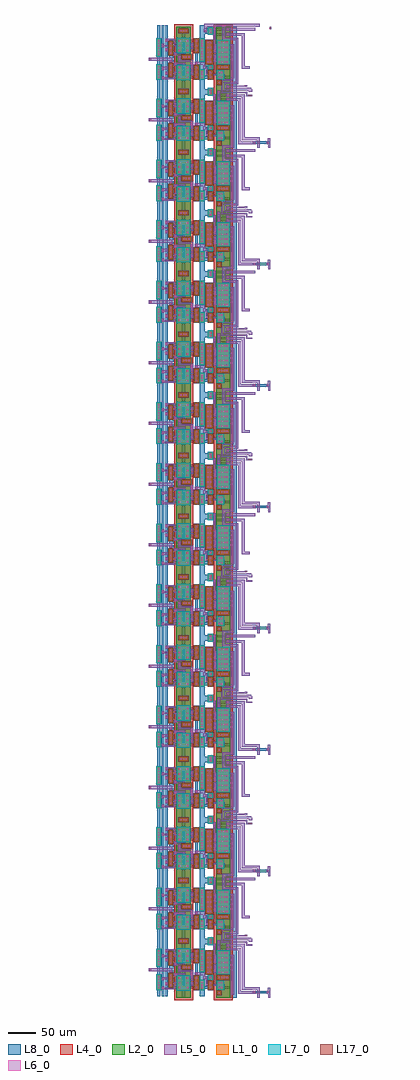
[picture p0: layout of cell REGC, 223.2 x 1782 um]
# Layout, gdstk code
from math import pi, radians
import gdstk
lib = gdstk.Library(unit=1e-6, precision=1e-09)
def R(c, l, rs):  # rectangles x0, y0, x1, y1
    for r in rs: c.add(gdstk.rectangle(r[:2], r[2:], *l))
def A(c, l, x, y, w, h, nx, ny, dx, dy):  # array of equal rectangles
    R(c, l, [(x+i*dx, y+j*dy, x+i*dx+w, y+j*dy+h) for i in range(nx) for j in range(ny)])
def P(c, l, *ps):  # polygons
    for p in ps: c.add(gdstk.Polygon(p, *l))
L1_0 = (1, 0)
L2_0 = (2, 0)
L4_0 = (4, 0)
L5_0 = (5, 0)
L6_0 = (6, 0)
L7_0 = (7, 0)
L8_0 = (8, 0)
L17_0 = (17, 0)

regbg = lib.new_cell('REGBG')
R(regbg, L1_0, [(44,8.4,51.2,20.4), (88,10.4,104.8,17.6), (58.8,28.8,66.4,69.6), (69.6,28.8,76.8,53.6), (138.4,28.8,145.6,60), (13.6,32,35.2,74.4), (44,32,55.6,74.4), (116.4,33.2,123.6,58), (83.2,58.4,100,65.6), (116.4,73.2,123.6,98), (138.4,76,145.6,102.4), (13.6,76.8,35.2,84), (44,76.8,51.2,84), (69.6,77.6,76.8,102.4), (58.8,85.6,66.4,102.4), (23.6,86.4,35.2,102.4), (44,86.4,51.2,102.4), (28,104.8,35.2,112)])
P(regbg, L1_0, [(107.6,103.2),(107.6,77.6),(100.4,77.6),(100.4,96.8),(92.8,96.8),(92.8,77.6),(85.6,77.6),(85.6,103.2)],
  [(107.6,28),(107.6,53.6),(100.4,53.6),(100.4,34.4),(92.8,34.4),(92.8,53.6),(85.6,53.6),(85.6,28)])
R(regbg, L2_0, [(11.6,6.4,37.2,117.2), (83.6,6.4,109.6,117.2)])
R(regbg, L4_0, [(7.2,2,41.6,121.6), (79.2,2,114,121.6)])
P(regbg, L5_0, [(78.8,88.8),(78.8,93.2),(67.6,93.2),(67.6,95.6),(94.8,95.6),(94.8,93.2),(84.4,93.2),(84.4,88.8)],
  [(160,68.8),(160,63.2),(117.2,63.2),(117.2,72),(122.8,72),(122.8,68.8)],
  [(124.8,91.2),(124.8,94.4),(130.4,94.4),(130.4,88.8),(111.2,88.8),(111.2,84.4),(98.4,84.4),(98.4,86.8),(108.8,86.8),(108.8,91.2)],
  [(84.4,70.4),(106.8,70.4),(106.8,59.2),(101.2,59.2),(101.2,67.2),(78.8,67.2),(78.8,82.4),(84.4,82.4)],
  [(108.8,58.8),(108.8,57.2),(94,57.2),(94,46.8),(67.6,46.8),(67.6,44.4),(96.4,44.4),(96.4,54.8),(108.8,54.8),(108.8,53.2),(114.4,53.2),(114.4,58.8)],
  [(131.6,85.6),(131.6,84),(124.8,84),(124.8,82.4),(114.4,82.4),(114.4,80),(137.2,80),(137.2,85.6)],
  [(78.8,42.4),(78.8,38),(67.6,38),(67.6,35.6),(94.8,35.6),(94.8,38),(84.4,38),(84.4,42.4)],
  [(131.6,40),(131.6,38),(137.2,38),(137.2,43.6),(131.6,43.6),(131.6,42.4),(111.2,42.4),(111.2,46.8),(98.4,46.8),(98.4,44.4),(108.8,44.4),(108.8,40)],
  [(36.4,58.8),(36.4,65.2),(11.6,65.2),(11.6,67.6),(36.4,67.6),(36.4,71.6),(42,71.6),(42,67.6),(57.6,67.6),(57.6,65.2),(42,65.2),(42,58.8),(57.6,58.8),(57.6,56.4),(11.6,56.4),(11.6,58.8)],
  [(94,84.4),(67.6,84.4),(67.6,86.8),(96.4,86.8),(96.4,76.4),(108.8,76.4),(108.8,78),(114.4,78),(114.4,72.4),(94,72.4)],
  [(60.8,84.4),(56.4,84.4),(56.4,95.6),(21.6,95.6),(21.6,93.2),(53.2,93.2),(53.2,79.2),(56.8,79.2),(56.8,70.8),(76,70.8),(76,76.4),(60.8,76.4)],
  [(131.6,96.8),(137.2,96.8),(137.2,102.4),(112,102.4),(112,95.6),(98.4,95.6),(98.4,93.2),(115.1,93.2),(115.1,99.2),(131.6,99.2)],
  [(130.4,34.4),(124.8,34.4),(124.8,32),(115.1,32),(115.1,38),(98.4,38),(98.4,35.6),(112,35.6),(112,28.8),(130.4,28.8)],
  [(130.4,45.6),(130.4,51.2),(114.4,51.2),(114.4,48.8),(124.8,48.8),(124.8,45.6)],
  [(57.6,38.8),(9.2,38.8),(9.2,41.2),(36.4,41.2),(36.4,47.6),(9.2,47.6),(9.2,50),(36.4,50),(36.4,54),(42,54),(42,50),(57.6,50),(57.6,47.6),(42,47.6),(42,41.2),(57.6,41.2)])
A(regbg, L6_0, 90.4, 12.8, 2.4, 2.4, 3, 1, 4.8, 0)
A(regbg, L6_0, 61.2, 31.2, 2.8, 2.4, 1, 8, 0, 4.8)
A(regbg, L6_0, 72, 31.2, 2.4, 2.4, 1, 3, 0, 8.8)
A(regbg, L6_0, 88, 31.2, 2.4, 2.4, 1, 3, 0, 8.8)
A(regbg, L6_0, 102.8, 31.2, 2.4, 2.4, 1, 3, 0, 8.8)
A(regbg, L6_0, 140.8, 31.2, 2.4, 2.4, 1, 6, 0, 4.8)
A(regbg, L6_0, 16, 34.4, 2.4, 2.4, 1, 3, 0, 8.8)
A(regbg, L6_0, 16, 34.4, 2.4, 2.4, 4, 5, 4.8, 8.8)
A(regbg, L6_0, 46.4, 34.4, 2.4, 2.4, 1, 5, 0, 8.8)
A(regbg, L6_0, 50.8, 34.4, 2.4, 2.4, 1, 5, 0, 8.8)
A(regbg, L6_0, 118.8, 35.6, 2.4, 2.4, 1, 3, 0, 8.8)
A(regbg, L6_0, 16, 52, 2.4, 2.4, 1, 3, 0, 8.8)
A(regbg, L6_0, 85.6, 60.8, 2.4, 2.4, 3, 1, 4.8, 0)
A(regbg, L6_0, 118.8, 75.6, 2.4, 2.4, 1, 3, 0, 8.8)
A(regbg, L6_0, 140.8, 78.4, 2.4, 2.4, 1, 5, 0, 4.8)
A(regbg, L6_0, 16, 79.2, 2.4, 2.4, 4, 1, 4.8, 0)
A(regbg, L6_0, 72, 80, 2.4, 2.4, 1, 3, 0, 8.8)
A(regbg, L6_0, 88, 80, 2.4, 2.4, 1, 3, 0, 8.8)
A(regbg, L6_0, 102.8, 80, 2.4, 2.4, 1, 3, 0, 8.8)
A(regbg, L6_0, 61.2, 88, 2.8, 2.4, 1, 3, 0, 4.8)
R(regbg, L6_0, [(46.4,10.8,48.8,13.2), (46.4,15.6,48.8,18), (126.4,30.4,128.8,32.8), (80.4,38.4,82.8,40.8), (133.2,39.6,135.6,42), (126.4,47.2,128.8,49.6), (38,50,40.4,52.4), (110.4,54.8,112.8,57.2), (102.8,60.8,105.2,63.2), (156,64.8,158.4,67.2), (38,67.6,40.4,70), (118.8,68,121.2,70.4), (72,72.4,74.4,74.8), (110.4,74,112.8,76.4), (80.4,78.4,82.8,80.8), (16,79.2,18.4,81.6), (46.4,79.2,48.8,81.6), (133.2,81.6,135.6,84), (26,88.8,28.4,91.2), (30.4,88.8,32.8,91.2), (46.4,88.8,48.8,91.2), (80.4,90.4,82.8,92.8), (126.4,90.4,128.8,92.8), (26,97.6,28.4,100), (30.4,97.6,32.8,100), (46.4,97.6,48.8,100), (133.2,98.4,135.6,100.8), (30.4,107.2,32.8,109.6)])
R(regbg, L7_0, [(42.8,7.2,52.4,21.6), (84.4,26.8,108.8,54.8), (57.6,27.6,67.6,70.8), (137.2,27.6,146.8,61.2), (12.4,30.8,36.4,75.6), (137.2,74.8,146.8,103.6), (42.8,75.6,52.4,85.2), (84.4,76.4,108.8,104.4), (57.6,84.4,67.6,103.6), (22.4,85.2,36.4,103.6)])
A(regbg, L8_0, 12, 33.2, 22, 4.8, 1, 3, 0, 17.6)
A(regbg, L8_0, 45.2, 33.2, 12.8, 4.8, 1, 3, 0, 17.6)
R(regbg, L8_0, [(125.2,4,130,114.8), (132,4,136.8,114.8), (139.2,4,144.8,114.8), (0,6.4,12,117.2), (70.8,30,91.6,34.8), (67.2,38.8,75.6,43.6), (12,78,34,82.8), (45.2,78,58,82.8), (67.2,87.6,75.6,92.4), (45.2,96.4,58,101.2), (70.8,96.4,91.6,101.2)])
P(regbg, L8_0, [(91.6,52.4),(75.6,52.4),(75.6,76),(70.8,76),(70.8,47.6),(79.2,47.6),(79.2,37.2),(84,37.2),(84,47.6),(91.6,47.6)],
  [(122.4,88),(122.4,83.2),(114,83.2),(114,72.8),(109.2,72.8),(109.2,87.6),(101.6,87.6),(101.6,92.4),(114,92.4),(114,88)],
  [(122.4,92),(122.4,101.2),(101.6,101.2),(101.6,96.4),(117.6,96.4),(117.6,92)],
  [(34,110.8),(34,96.4),(12,96.4),(12,101.2),(29.2,101.2),(29.2,110.8)],
  [(84,78.8),(84,77.2),(79.2,77.2),(79.2,78.8),(70.8,78.8),(70.8,83.6),(79.2,83.6),(79.2,94),(84,94),(84,83.6),(91.6,83.6),(91.6,78.8)],
  [(122.4,66.8),(101.6,66.8),(101.6,83.6),(106.4,83.6),(106.4,70.8),(117.6,70.8),(117.6,79.2),(122.4,79.2)],
  [(93.6,11.6),(89.2,11.6),(89.2,16.4),(93.6,16.4),(93.6,38.8),(86.8,38.8),(86.8,43.8),(93.6,43.8),(93.6,59.6),(84.4,59.6),(84.4,64.4),(93.6,64.4),(93.6,87.6),(86.8,87.6),(86.8,92.4),(93.6,92.4),(93.6,117.2),(99.6,117.2),(99.6,16.4),(103.6,16.4),(103.6,11.6),(99.6,11.6),(99.6,6.4),(93.6,6.4)],
  [(122.4,43.2),(122.4,48),(114,48),(114,58.4),(109.2,58.4),(109.2,43.6),(101.6,43.6),(101.6,38.8),(114,38.8),(114,43.2)],
  [(122.4,39.2),(122.4,30),(101.6,30),(101.6,34.8),(117.6,34.8),(117.6,39.2)],
  [(122.4,64.4),(101.6,64.4),(101.6,47.6),(106.4,47.6),(106.4,60.4),(117.6,60.4),(117.6,52),(122.4,52)],
  [(41.6,59.6),(41.6,48.8),(36.8,48.8),(36.8,59.6),(14.8,59.6),(14.8,64.4),(54.4,64.4),(54.4,59.6)],
  [(67.2,114.8),(67.2,4),(58,4),(58,9.6),(44.8,9.6),(44.8,19.6),(58,19.6),(58,114.8)],
  [(41.6,87.6),(41.6,66.4),(36.8,66.4),(36.8,87.6),(24.4,87.6),(24.4,92.4),(50,92.4),(50,87.6)],
  [(40.8,42),(40.8,32.4),(36.8,32.4),(36.8,42),(14.8,42),(14.8,46.8),(54.4,46.8),(54.4,42)])
R(regbg, L17_0, [(86.8,9.2,106,18.8), (68.4,27.6,78,54.8), (42.8,30.8,56.8,75.6), (115.2,32,124.8,59.2), (82,57.2,101.2,66.8), (115.2,72,124.8,99.2), (12.4,75.6,36.4,85.2), (68.4,76.4,78,103.6), (42.8,85.2,52.4,103.6), (26.8,103.6,36.4,113.2)])
regbg.add(gdstk.Label('REGBG', (167.6,65.6), layer=58, texttype=0))
regbg.add(gdstk.Label('HB', (134.4,111.85), layer=59, texttype=0))
regbg.add(gdstk.Label('H', (127.55,110.95), layer=59, texttype=0))
regbg.add(gdstk.Label('VDD', (96.6,23.05), layer=60, texttype=0))
regbg.add(gdstk.Label('VSS', (62.4,21.35), layer=60, texttype=0))
regbg.add(gdstk.Label('VDD', (6.4,57.2), layer=60, texttype=0))
regbg.add(gdstk.Label('VSS', (142.4,22.15), layer=60, texttype=0))

doublregbg = lib.new_cell('DOUBLREGBG')
R(doublregbg, L5_0, [(178.4,10.4,183.6,15.6), (105.6,81.6,110.8,101.6), (113.6,89.2,118.8,108), (129.6,89.2,134.8,94.4), (129.6,96.4,134.8,101.6), (129.6,112.4,134.8,118), (105.6,192.4,110.8,222.4), (129.6,208,134.8,213.2), (129.6,217.2,134.8,222.4)])
P(doublregbg, L5_0, [(209.6,21.2),(209.6,3.2),(206.4,3.2),(206.4,10.4),(203.6,10.4),(203.6,15.6),(205.2,15.6),(205.2,21.2)])
R(doublregbg, L6_0, [(180,12,182,14), (205.2,12,207.2,14), (115.2,90.8,117.2,92.8), (131.2,90.8,133.2,92.8), (107.2,98,109.2,100), (131.2,98,133.2,100), (115.2,104.4,117.2,106.4), (131.2,114,133.2,116), (131.2,209.6,133.2,211.6), (107.2,218.8,109.2,220.8), (131.2,218.8,133.2,220.8)])
R(doublregbg, L8_0, [(178.4,10.8,208.4,15.2), (106,96.8,134.4,101.2), (106,217.6,134.4,222)])
P(doublregbg, L8_0, [(111.6,89.6),(111.6,88),(107.6,88),(107.6,94),(134.4,94),(134.4,89.6)],
  [(134.4,117.2),(134.4,103.2),(114,103.2),(114,107.6),(130,107.6),(130,117.2)],
  [(111.6,208.4),(111.6,198.8),(107.6,198.8),(107.6,212.8),(134.4,212.8),(134.4,208.4)])
doublregbg.add(gdstk.FlexPath([(134.8,91.6),(153.6,91.6),(153.6,12.8),(178.4,12.8)], 4.8, ends="flush", simple_path=True, layer=5, datatype=0))  # L5_0
doublregbg.add(gdstk.FlexPath([(134.8,98.8),(160.8,98.8),(160.8,20),(188.8,20),(188.8,3.2)], 4.8, ends="flush", simple_path=True, layer=5, datatype=0))  # L5_0
doublregbg.add(gdstk.FlexPath([(141.6,8),(141.6,81.6)], 4.8, ends="flush", simple_path=True, layer=5, datatype=0))  # L5_0
doublregbg.add(gdstk.FlexPath([(134.8,116),(164.8,116),(164.8,116.8),(168.4,116.8)], 2.4, ends="flush", simple_path=True, layer=5, datatype=0))  # L5_0
doublregbg.add(gdstk.FlexPath([(134.8,210.4),(160.8,210.4),(160.8,150.4),(172.4,150.4)], 4.8, ends="flush", simple_path=True, layer=5, datatype=0))  # L5_0
doublregbg.add(gdstk.FlexPath([(134.8,220),(182.4,220)], 4.8, ends="flush", simple_path=True, layer=5, datatype=0))  # L5_0
doublregbg.add(gdstk.FlexPath([(137.2,121.6),(126.4,121.6),(126.4,109.2),(137.2,109.2)], 2.4, ends="flush", simple_path=True, layer=5, datatype=0))  # L5_0
doublregbg.add(gdstk.FlexPath([(177.2,99.2),(167.2,99.2),(167.2,104.8),(122,104.8),(122,127.2),(141.6,127.2),(141.6,130.4)], 2.4, ends="flush", simple_path=True, layer=5, datatype=0))  # L5_0
doublregbg.add(gdstk.FlexPath([(141.6,130.4),(141.6,192.4)], 4.8, ends="flush", simple_path=True, layer=5, datatype=0))  # L5_0
doublregbg.add(gdstk.FlexPath([(137.2,110.4),(172.8,110.4),(172.8,108),(177.2,108)], 4.8, ends="flush", simple_path=True, layer=5, datatype=0))  # L5_0
doublregbg.add(gdstk.FlexPath([(137.2,121.6),(149.6,121.6),(149.6,202.4),(125.2,202.4),(125.2,227.2),(144,227.2)], 4.8, ends="flush", simple_path=True, layer=5, datatype=0))  # L5_0
doublregbg.add(gdstk.Reference(regbg, (148.4,231.2), rotation=pi))
doublregbg.add(gdstk.Reference(regbg, (148.4,120.4), rotation=pi))
doublregbg.add(gdstk.Label('C(2P)', (5.2,165.6), layer=59, texttype=0))
doublregbg.add(gdstk.Label('C(2P#1)\r', (11.2,54.8), layer=59, texttype=0))
doublregbg.add(gdstk.Label('C2P', (115.6,220), layer=59, texttype=0))
doublregbg.add(gdstk.Label('C2PB', (115.2,210.8), layer=59, texttype=0))
doublregbg.add(gdstk.Label('C2P#1', (123.6,99.2), layer=59, texttype=0))
doublregbg.add(gdstk.Label('C2P#1B', (123.6,92), layer=59, texttype=0))
doublregbg.add(gdstk.Label('DOUBLREGBG', (71.6,250.4), layer=58, texttype=0))

regc = lib.new_cell('REGC')
R(regc, L5_0, [(88.8,1748.4,94.4,1754), (208.8,1753.6,211.6,1758.8)])
R(regc, L6_0, [(90.4,1750,92.8,1752.4), (208,1755.2,210,1757.2)])
regc.add(gdstk.FlexPath([(91.6,1754),(91.6,1761.2),(122.8,1761.2)], 4.8, ends="flush", simple_path=True, layer=5, datatype=0))  # L5_0
regc.add(gdstk.FlexPath([(144,1761.2),(191.2,1761.2)], 4.8, ends="flush", simple_path=True, layer=5, datatype=0))  # L5_0
r = gdstk.Reference(doublregbg, (0,-17.2)); r.repetition = gdstk.Repetition(1, 8, v1=(0,0), v2=(0,221.6)); regc.add(r)

lib.write_gds('REGC.gds')
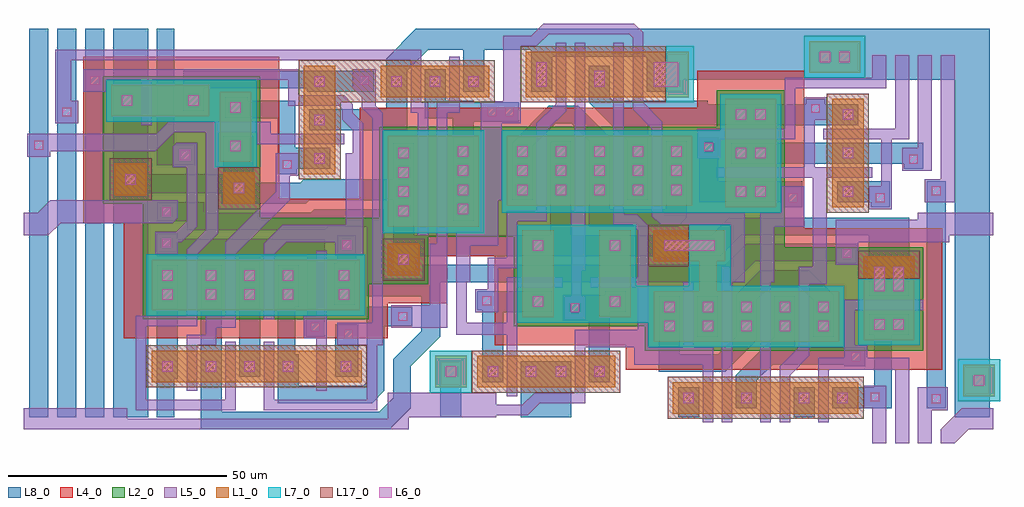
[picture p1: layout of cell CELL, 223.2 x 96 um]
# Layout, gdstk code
import gdstk
lib = gdstk.Library(unit=1e-6, precision=1e-09)
def R(c, l, rs):  # rectangles x0, y0, x1, y1
    for r in rs: c.add(gdstk.rectangle(r[:2], r[2:], *l))
def A(c, l, x, y, w, h, nx, ny, dx, dy):  # array of equal rectangles
    R(c, l, [(x+i*dx, y+j*dy, x+i*dx+w, y+j*dy+h) for i in range(nx) for j in range(ny)])
def P(c, l, *ps):  # polygons
    for p in ps: c.add(gdstk.Polygon(p, *l))
L1_0 = (1, 0)
L2_0 = (2, 0)
L4_0 = (4, 0)
L5_0 = (5, 0)
L6_0 = (6, 0)
L7_0 = (7, 0)
L8_0 = (8, 0)
L17_0 = (17, 0)

fonct0 = lib.new_cell('FONCT0')
R(fonct0, L1_0, [(92.8,-82,100,-74.8), (28,-80.8,76,-73.6), (28,-64.4,75.6,-52.8), (82,-56.4,89.2,-49.2), (82,-45.2,102.8,-24.4), (44.4,-40,51.6,-32.8), (19.6,-38,26.8,-30.8), (62.8,-33.2,70,-8.4), (43.6,-30.4,50.8,-14.4), (18.8,-20,41.2,-12.8), (80.4,-15.6,105.2,-8.4)])
P(fonct0, L2_0, [(16.8,-10.8),(16.8,-40),(26,-40),(26,-66.4),(77.6,-66.4),(77.6,-58.4),(91.2,-58.4),(91.2,-47.6),(106,-47.6),(106,-22.4),(80,-22.4),(80,-43.2),(52.8,-43.2),(52.8,-10.8)])
P(fonct0, L4_0, [(57.2,-6.4),(12.4,-6.4),(12.4,-44.4),(21.6,-44.4),(21.6,-70.8),(82,-70.8),(82,-62.8),(95.6,-62.8),(95.6,-52),(110.4,-52),(110.4,-18),(75.6,-18),(75.6,-38.8),(57.2,-38.8)])
R(fonct0, L5_0, [(56.4,-33.6,61.6,-28.4)])
P(fonct0, L5_0, [(91.6,-63.2),(91.6,-49.2),(93.2,-49.2),(93.2,-16.8),(96,-16.8),(96,-6.4),(98.4,-6.4),(98.4,-19.2),(95.6,-19.2),(95.6,-68.4),(82.8,-68.4),(82.8,-63.2)],
  [(80.8,-72.4),(70.4,-72.4),(70.4,-67.2),(78.4,-67.2),(78.4,-20.4),(76,-18),(76,-15.6),(74,-13.6),(74,-9.2),(79.2,-9.2),(79.2,-17.6),(80.8,-19.2)],
  [(-1.2,-47.2),(4.4,-47.2),(7.2,-44.4),(32.8,-44.4),(34,-43.2),(34,-39.2),(4.8,-39.2),(2,-42),(-1.2,-42)],
  [(76.4,-51.8),(70,-51.8),(70,-48.8),(58.8,-48.8),(56,-51.6),(56,-66.4),(53.6,-66.4),(53.6,-49.2),(58,-44.8),(76.4,-44.8)],
  [(79.6,-87.2),(79.6,-72.4),(77.2,-72.4),(77.2,-84.8),(56,-84.8),(56,-71.6),(53.6,-71.6),(53.6,-87.2)],
  [(40.4,-70),(40.4,-65.6),(44.8,-65.6),(44.8,-48.8),(56.4,-37.2),(56.4,-33.6),(59.6,-33.6),(59.6,-39.2),(47.2,-51.6),(47.2,-68.4),(42.8,-68.4),(42.8,-72.4),(38.4,-72.4),(38.4,-82.8),(36,-82.8),(36,-70)],
  [(68,-82.8),(68,-50.8),(65.6,-50.8),(65.6,-65.6),(62.8,-65.6),(62.8,-70.8),(65.6,-70.8),(65.6,-82.8)],
  [(36,-31.6),(32.8,-31.6),(32.8,-26.8),(33.6,-26),(38.4,-26),(38.4,-45.2),(34.8,-48.8),(34,-48.8),(34,-51.6),(28.8,-51.6),(28.8,-46.4),(33.6,-46.4),(36,-44)],
  [(40.4,-23.6),(40.4,-46),(36,-50.4),(36,-65.6),(24.4,-65.6),(24.4,-87.2),(47.2,-87.2),(47.2,-71.6),(44.8,-71.6),(44.8,-84.8),(26.8,-84.8),(26.8,-68),(38.4,-68),(38.4,-51.6),(43.2,-46.8),(43.2,-23.6)],
  [(11.2,-16.4),(9.6,-16.4),(9.6,-7.2),(87.2,-7.2),(87.2,-19.2),(88.8,-19.2),(88.8,-47.2),(91.2,-47.2),(91.2,-16.8),(89.6,-16.8),(89.6,-4.8),(6,-4.8),(6,-21.6),(11.2,-21.6)],
  [(55.2,-24),(72,-24),(72,-26.4),(52,-26.4),(52,-23.6),(33.2,-23.6),(28.8,-28),(4.8,-28),(4.8,-29.2),(-0.4,-29.2),(-0.4,-24),(29,-24),(31.8,-21.2),(55.2,-21.2)],
  [(106.8,-83.2),(106.8,-88.8),(86.8,-88.8),(86.8,-91.6),(-1.2,-91.6),(-1.2,-86.8),(22.4,-86.8),(22.4,-89.2),(82,-89.2),(82,-83.2)],
  [(74,-28.4),(74,-23.2),(71.6,-20.8),(71.6,-18.4),(70.8,-17.6),(59.2,-17.6),(59.2,-11.6),(28,-11.6),(28,-22),(25.6,-22),(25.6,-11.6),(17.6,-11.6),(17.6,-14.4),(12.4,-14.4),(12.4,-9.2),(61.6,-9.2),(61.6,-15.2),(72,-15.2),(74,-17.2),(74,-19.2),(76.4,-21.6),(76.4,-44.8),(72.4,-44.8),(72.4,-28.4)])
A(fonct0, L6_0, 40.4, -78.4, 2.4, 2.4, 3, 2, 8.8, 16.4)
A(fonct0, L6_0, 40.4, -57.6, 2.4, 2.4, 3, 1, 8.8, 0)
A(fonct0, L6_0, 84.4, -42.8, 2.4, 2.4, 1, 4, 0, 4.4)
A(fonct0, L6_0, 98, -42.4, 2.4, 2.4, 1, 4, 0, 4.4)
A(fonct0, L6_0, 65.2, -30.8, 2.4, 2.4, 1, 3, 0, 8.8)
A(fonct0, L6_0, 82.8, -13.2, 2.4, 2.4, 3, 1, 8.8, 0)
R(fonct0, L6_0, [(95.2,-79.6,97.6,-77.2), (30.4,-78.4,32.8,-76), (71.2,-78.4,73.6,-76), (72,-70.8,74,-68.8), (64.4,-69.2,66.4,-67.2), (84.4,-66.8,86.4,-64.8), (30.4,-62,32.8,-59.6), (70.8,-62,73.2,-59.6), (30.4,-57.6,32.8,-55.2), (70.8,-57.6,73.2,-55.2), (84.4,-54,86.8,-51.6), (71.6,-50.4,73.6,-48.4), (30.4,-50,32.4,-48), (30.4,-42.8,32.4,-40.8), (46.8,-37.6,49.2,-35.2), (22,-35.6,24.4,-33.2), (58,-32,60,-30), (34.4,-30,36.8,-27.6), (46,-28,48.4,-25.6), (1.2,-27.6,3.2,-25.6), (7.6,-20,9.6,-18), (46,-19.2,48.4,-16.8), (21.2,-17.6,23.6,-15.2), (36.4,-17.6,38.8,-15.2), (14,-12.8,16,-10.8), (75.6,-12.8,77.6,-10.8)])
R(fonct0, L7_0, [(91.6,-83.2,101.2,-73.6), (26.8,-65.6,76.8,-51.6), (80.8,-46.8,104,-23.2)])
P(fonct0, L7_0, [(17.6,-11.6),(17.6,-21.2),(42.4,-21.2),(42.4,-31.6),(52,-31.6),(52,-11.6)])
A(fonct0, L8_0, 0, -88.8, 4.4, 88.8, 3, 1, 6.4, 0)
R(fonct0, L8_0, [(94,-88.8,98.8,-76), (39.2,-79.6,44,-54), (70,-79.6,75.2,-67.6)])
P(fonct0, L8_0, [(33.2,-88.8),(33.2,-80),(34,-80),(34,-54),(29.2,-54),(29.2,-88.8)],
  [(33.2,-26.4),(38,-26.4),(38,-31.2),(29.2,-31.2),(29.2,0),(33.2,0)],
  [(61.6,-74.4),(60.8,-74.4),(60.8,-63.6),(61.6,-63.6),(61.6,-54),(56.8,-54),(56.8,-85.6),(78.4,-85.6),(81.2,-82.8),(81.2,-68),(87.6,-68),(87.6,-63.6),(77.2,-63.6),(77.2,-80.8),(76.4,-81.6),(61.6,-81.6)],
  [(60.8,-16.4),(50,-16.4),(50,-15.6),(44.8,-15.6),(44.8,-20.4),(56.8,-20.4),(56.8,-33.2),(61.2,-33.2),(61.2,-32),(68.8,-32),(68.8,-27.2),(60.8,-27.2)],
  [(40,-18.8),(40,-13.6),(63.6,-13.6),(63.6,-14.4),(78.8,-14.4),(78.8,-9.6),(35.2,-9.6),(35.2,-18.8)],
  [(106.8,-4.8),(106.8,0),(88.4,0),(81.6,-6.8),(81.6,-18.4),(64,-18.4),(64,-23.2),(86.4,-23.2),(86.4,-9.6),(91.2,-4.8),(99.2,-4.8),(99.2,-14.4),(104,-14.4),(104,-4.8)],
  [(69.6,-53.6),(69.6,-63.2),(74.4,-63.2),(74.4,-53.6),(74.8,-53.6),(74.8,-47.2),(70.4,-47.2),(70.4,-53.6)],
  [(101.6,-44),(101.6,-16.4),(95.2,-16.4),(95.2,-9.2),(90.4,-9.2),(90.4,-20.4),(96.8,-20.4),(96.8,-44)],
  [(67.6,-70.4),(63.2,-70.4),(63.2,-65.6),(63.6,-65.6),(63.6,-52),(52.8,-52),(52.8,-79.6),(48,-79.6),(48,-52),(29.2,-52),(29.2,-46.8),(34,-46.8),(34,-48),(67.6,-48)],
  [(94,-58),(94,-70.4),(87.2,-77.2),(87.2,-86.8),(82.4,-91.6),(39.2,-91.6),(39.2,-79.6),(44,-79.6),(44,-87.6),(80,-87.6),(83.2,-84.4),(83.2,-75.6),(89.6,-69.2),(89.6,-61.2),(77.2,-61.2),(77.2,-45.2),(68.4,-45.2),(67.6,-46),(36,-46),(36,-44),(29.2,-44),(29.2,-39.6),(40,-39.6),(40,-42),(64.4,-42),(65.2,-41.2),(81.2,-41.2),(81.2,-57.2),(90,-57.2),(90,-54),(106.8,-54),(106.8,-58)],
  [(44.4,-33.2),(44.4,-24.4),(51.2,-24.4),(51.2,-35.2),(62,-35.2),(62.8,-34.4),(83.2,-34.4),(83.2,-26),(88,-26),(88,-47.2),(106.8,-47.2),(106.8,-52),(88,-52),(88,-55.2),(83.2,-55.2),(83.2,-39.2),(64,-39.2),(63.2,-40),(44,-40),(44,-37.6),(27.2,-37.6),(27.2,-88.8),(19.2,-88.8),(19.2,0),(27.2,0),(27.2,-33.2)])
R(fonct0, L17_0, [(26.8,-82,77.2,-72.4), (80.8,-57.6,90.4,-48), (43.2,-41.2,52.8,-31.6), (18.4,-39.2,28,-29.6)])
P(fonct0, L17_0, [(61.6,-7.2),(61.6,-34.4),(71.2,-34.4),(71.2,-16.8),(106.4,-16.8),(106.4,-7.2)])
fonct0.add(gdstk.Label('N', (8.8,-33.2), layer=59, texttype=0))
fonct0.add(gdstk.Label('2MQ-1', (31.6,-4.8), layer=59, texttype=0))
fonct0.add(gdstk.Label('SMQ', (31.6,-84.8), layer=59, texttype=0))
fonct0.add(gdstk.Label('_\rC', (14,-33.2), layer=59, texttype=0))
fonct0.add(gdstk.Label('SFQ', (99.2,-21.2), layer=59, texttype=0))
fonct0.add(gdstk.Label('_\rD', (1.2,-33.2), layer=59, texttype=0))
fonct0.add(gdstk.Label('VDD', (23.2,-57.6), layer=60, texttype=0))
fonct0.add(gdstk.Label('VSS', (101.6,-4), layer=60, texttype=0))

add0 = lib.new_cell('ADD0')
R(add0, L1_0, [(39.2,-88,81.6,-80.8), (105.6,-84,112.8,-76.8), (-5.6,-82,26,-74.8), (34.8,-71.6,77.2,-60), (82.8,-71.2,94.4,-52), (4.8,-66,12,-46), (4.8,-66,12,-46), (22.4,-66,29.6,-46), (51.2,-40.8,62.8,-16), (75.6,-40.8,82.8,-16), (1.2,-40.4,43.6,-24.4), (5.6,-15.6,42.8,-5.2), (70.4,-10,82,-2.8)])
P(add0, L1_0, [(34.8,-46),(51.2,-46),(51.2,-53.2),(49.2,-53.2),(49.2,-60),(45.2,-60),(45.2,-53.2),(34.8,-53.2)])
P(add0, L2_0, [(49.2,-14),(49.2,-22.4),(-2,-22.4),(-2,-47.6),(2.8,-47.6),(2.8,-68),(32.8,-68),(32.8,-73.6),(96.4,-73.6),(96.4,-50),(64.8,-50),(64.8,-14)])
P(add0, L4_0, [(69.2,-9.6),(44.8,-9.6),(44.8,-18),(-6.4,-18),(-6.4,-52),(-1.6,-52),(-1.6,-72.4),(28.4,-72.4),(28.4,-78),(100.8,-78),(100.8,-45.6),(69.2,-45.6)])
R(add0, L5_0, [(46,-90,48.4,-76.8), (50.4,-90,52.8,-58), (59.2,-90,61.6,-58), (1.2,-84,3.6,-59.2), (41.6,-72.8,44,-58), (14.4,-66.4,19.2,-61.2), (1.2,-59.2,14,-56.8)])
P(add0, L5_0, [(89.2,-25.2),(86.8,-25.2),(86.8,-36),(84,-36),(84,-41.2),(89.2,-41.2)],
  [(93.2,-25.2),(73.6,-25.2),(73.6,-22.8),(90,-22.8),(90,-6),(93.2,-6)],
  [(98.4,-6),(95.2,-6),(95.2,-27.2),(91.6,-27.2),(91.6,-32.4),(98.4,-32.4)],
  [(112.4,-91.6),(112.4,-86.8),(105.2,-86.8),(100.4,-91.6),(100.4,-94.8),(103.6,-94.8),(106.8,-91.6)],
  [(19.2,-3.2),(16.8,-3.2),(16.8,-41.6),(16,-41.6),(16,-61.2),(18.4,-61.2),(18.4,-55.2),(19.2,-55.2)],
  [(93.2,-75.2),(93.2,-94.8),(90,-94.8),(90,-78),(74.8,-78),(74.8,-90),(72.4,-90),(72.4,-75.2),(78.4,-75.2),(78.4,-62),(96.4,-62),(96.4,-64.4),(80.8,-64.4),(80.8,-72.4),(83.6,-72.4),(83.6,-75.2)],
  [(19.2,-72.8),(30.4,-72.8),(30.4,-76.8),(48.4,-76.8),(48.4,-72.8),(33.6,-72.8),(33.6,-56.8),(20.4,-56.8),(20.4,-59.2),(31.2,-59.2),(31.2,-68.8),(16.8,-68.8),(16.8,-83.2),(7.6,-83.2),(4.8,-86),(-1.2,-86),(-1.2,-88.4),(6,-88.4),(8.8,-85.6),(19.2,-85.6)],
  [(33.6,-56.8),(33.6,-45),(31,-42.4),(28,-42.4),(28,-3.2),(25.6,-3.2),(25.6,-44.8),(30,-44.8),(31.2,-46),(31.2,-56.8)],
  [(95.2,-42),(95.2,-43.6),(76.4,-43.6),(76.4,-54),(81.6,-54),(81.6,-48.8),(102.4,-48.8),(102.4,-47.2),(112.4,-47.2),(112.4,-42)],
  [(71.6,-31.6),(84.8,-31.6),(84.8,-34),(49.2,-34),(49.2,-31.6),(69.2,-31.6),(69.2,-15.6),(74.4,-15.6),(74.4,-20.8),(71.6,-20.8)],
  [(95.2,-94.8),(98.4,-94.8),(98.4,-87.2),(102,-87.2),(102,-82),(95.2,-82)],
  [(-0.8,-49.6),(-0.8,-39.2),(0,-39.2),(0,-21.6),(4.4,-21.6),(4.4,-4),(8,-4),(10.8,-1.2),(29.2,-1.2),(30,-2),(30,-4.4),(32.4,-4.4),(32.4,-0.8),(30.4,1.2),(9.6,1.2),(6.8,-1.6),(0.4,-1.6),(0.4,-16.6),(-4.8,-16.6),(-4.8,-46.4),(-10.4,-46.4),(-10.4,-70),(1.2,-70),(1.2,-67.2),(-8,-67.2),(-8,-58),(-7.2,-58),(-7.2,-49.6)],
  [(88,-81.6),(88,-94.8),(84.8,-94.8),(84.8,-86.8),(82.8,-86.8),(82.8,-81.6)],
  [(1.2,-41.6),(8,-41.6),(8,-21.6),(12.4,-17.2),(12.4,-3.2),(14.8,-3.2),(14.8,-18.8),(10.4,-23.2),(10.4,-44),(3.6,-44),(3.6,-54.8),(-0.8,-54.8),(-0.8,-64.8),(-6,-64.8),(-6,-59.6),(-3.2,-59.6),(-3.2,-52.4),(1.2,-52.4)],
  [(103.6,-6),(100.4,-6),(100.4,-34.4),(96.8,-34.4),(96.8,-39.6),(103.6,-39.6)],
  [(69.2,-36),(64,-36),(64,-42),(59.2,-42),(59.2,-58),(62.4,-58),(62.4,-45.2),(69.2,-45.2)],
  [(74.4,-34),(74.4,-58.4),(70.4,-58.4),(70.4,-74.8),(66,-79.2),(66,-90),(63.6,-90),(63.6,-77.2),(68,-72.8),(68,-54.4),(71.2,-54.4),(71.2,-34)],
  [(50.4,-58),(50.4,-54.4),(52.4,-54.4),(52.4,-44.8),(36.4,-44.8),(34.4,-42.8),(34.4,-22.8),(30,-18.4),(30,-4.4),(32.4,-4.4),(32.4,-16.8),(36.8,-21.2),(36.8,-41.6),(37.2,-42),(55.6,-42),(55.6,-58)],
  [(50,-25.2),(50,-29.6),(44.8,-29.6),(44.8,-22.8),(64.8,-22.8),(64.8,-11.2),(84.8,-11.2),(84.8,-6),(88,-6),(88,-13.6),(67.2,-13.6),(67.2,-25.2)])
A(add0, L6_0, 41.6, -85.6, 2.4, 2.4, 3, 1, 13.2, 0)
A(add0, L6_0, 37.2, -69.2, 2.4, 2.4, 5, 2, 8.8, 4.4)
A(add0, L6_0, 53.6, -38.4, 2.4, 2.4, 1, 3, 0, 8.8)
A(add0, L6_0, 58, -38.4, 2.4, 2.4, 1, 3, 0, 8.8)
A(add0, L6_0, 78, -38.4, 2.4, 2.4, 1, 3, 0, 8.8)
A(add0, L6_0, 3.6, -38, 2.4, 2.4, 5, 3, 8.8, 4.4)
R(add0, L6_0, [(76.8,-85.6,79.2,-83.2), (98.4,-85.6,100.4,-83.6), (84.4,-85.2,86.4,-83.2), (108,-81.6,110.4,-79.2), (-3.2,-79.6,-0.8,-77.2), (5.6,-79.6,8,-77.2), (12.4,-79.6,14.8,-77.2), (21.2,-79.6,23.6,-77.2), (80,-76,82,-74), (85.2,-68.8,87.6,-66.4), (89.6,-68.8,92,-66.4), (15.8,-64.8,17.8,-62.8), (7.2,-63.6,9.6,-61.2), (24.8,-63.6,27.2,-61.2), (-4.4,-63.2,-2.4,-61.2), (85.2,-60,87.6,-54.4), (89.6,-60,92,-54.4), (78,-52.4,80,-50.4), (7.2,-50.8,9.6,-48.4), (24.8,-50.8,27.2,-48.4), (37.2,-50.8,48.8,-48.4), (65.6,-39.6,67.6,-37.6), (85.6,-39.6,87.6,-37.6), (98.4,-38,100.4,-36), (93.2,-30.8,95.2,-28.8), (46.4,-28,48.4,-26), (-3.2,-20,-1.2,-18), (0.8,-20,2.8,-18), (70.8,-19.2,72.8,-17.2), (8,-13.2,10.4,-7.6), (21.2,-13.2,23.6,-9.6), (34.8,-13.2,40.4,-7.6), (72.8,-7.6,75.2,-5.2), (77.2,-7.6,79.6,-5.2)])
R(add0, L7_0, [(104.4,-85.2,114,-75.6), (81.6,-72.4,95.6,-57.2), (37.6,-16.8,44,-4), (69.2,-11.2,83.2,-1.6)])
P(add0, L7_0, [(50,-14.8),(50,-23.2),(0,-23.2),(0,-42),(64,-42),(64,-14.8)],
  [(42.8,-58.8),(42.8,-44.8),(52.4,-44.8),(52.4,-58.8),(78.4,-58.8),(78.4,-72.8),(33.6,-72.8),(33.6,-67.2),(3.6,-67.2),(3.6,-44.8),(30.8,-44.8),(30.8,-58.8)])
R(add0, L8_0, [(4.4,-88.8,16,-76), (40.4,-88.8,45.2,-82), (66.8,-88.8,71.6,-82), (97.2,-86.8,101.6,-34.8), (44.8,-70.4,49.6,-61.2), (-6.4,-21.2,4,-16.8)])
P(add0, L8_0, [(42.4,-25.6),(42.4,-43.2),(40.4,-45.2),(20,-45.2),(20,-25.6),(16,-21.6),(12.4,-21.6),(7.2,-26.8),(7.2,-39.2),(2.4,-39.2),(2.4,-26),(10.8,-17.6),(17.6,-17.6),(24.8,-24.8),(24.8,-41.2),(37.6,-41.2),(37.6,-25.6)],
  [(92,-30.8),(52.4,-30.8),(52.4,-26),(96.4,-26),(96.4,-32),(92,-32)],
  [(84,-65.2),(93.2,-65.2),(93.2,-70),(89.2,-70),(89.2,-86.8),(75.6,-86.8),(75.6,-82),(85.2,-82),(85.2,-70),(84,-70)],
  [(76.8,-39.6),(84.4,-39.6),(84.4,-40.8),(88.8,-40.8),(88.8,-34.8),(76.8,-34.8)],
  [(76,-70.4),(76,-60.8),(70.4,-55.2),(59.2,-55.2),(53.6,-60.8),(53.6,-70.4),(49.6,-74.4),(40.8,-74.4),(40.8,-61.2),(36,-61.2),(36,-78.4),(51.2,-78.4),(58.4,-71.2),(58.4,-62),(61.2,-59.2),(68.4,-59.2),(71.2,-62),(71.2,-70.4)],
  [(83.2,-72.8),(83.2,-77.2),(78.4,-77.2),(78.4,-76.8),(62,-76.8),(58.4,-80.4),(58.4,-86.8),(53.6,-86.8),(53.6,-79.2),(62.4,-70.4),(62.4,-61.2),(67.2,-61.2),(67.2,-72.8)],
  [(24.8,-64.8),(24.8,-80.8),(20,-80.8),(20,-66.8),(14,-66.8),(14,-60.8),(23.6,-60.8),(23.6,-60),(28.4,-60),(28.4,-64.8)],
  [(-1.2,-58),(53.2,-58),(58,-53.2),(76.4,-53.2),(76.4,-53.6),(81.2,-53.6),(81.2,-49.2),(56,-49.2),(51.2,-54),(-1.2,-54)],
  [(-1.2,-4.8),(6.8,-4.8),(6.8,-14.4),(11.6,-14.4),(11.6,-6.4),(33.2,-6.4),(33.2,-14.4),(41.6,-14.4),(41.6,-11.6),(103.6,-11.6),(103.6,-88.8),(111.6,-88.8),(111.6,0),(-1.2,0)],
  [(-1.2,-52),(50,-52),(54.8,-47.2),(84,-47.2),(84,-61.2),(93.2,-61.2),(93.2,-43.2),(52,-43.2),(48,-47.2),(16,-47.2),(16,-25.6),(11.6,-25.6),(11.2,-26),(11.2,-47.2),(-1.2,-47.2)],
  [(0.4,-80.8),(0.4,-64.8),(11.6,-64.8),(11.6,-60),(-5.6,-60),(-5.6,-64.4),(-4.4,-64.4),(-4.4,-80.8)],
  [(68.8,-34.8),(68.8,-40.8),(64,-40.8),(64,-39.6),(45.2,-39.6),(45.2,-24.8),(49.6,-24.8),(49.6,-34.8)],
  [(81.6,-22),(33.6,-22),(33.6,-39.2),(28.8,-39.2),(28.8,-25.6),(20,-16.8),(20,-8.4),(24.8,-8.4),(24.8,-15.6),(25.6,-16.4),(47.2,-16.4),(47.2,-17.2),(69.6,-17.2),(69.6,-16),(74,-16),(74,-17.2),(81.6,-17.2)])
R(add0, L17_0, [(38,-89.2,82.8,-79.6), (-6.8,-83.2,27.2,-73.6), (81.6,-57.2,95.6,-50.8), (33.6,-54.4,42.8,-44.8), (74.4,-42,84,-14.8), (4.4,-16.8,37.6,-4)])
add0.add(gdstk.Label('VSS', (108,-63.2), layer=60, texttype=0))
add0.add(gdstk.Label('VSS\r', (48,-2.8), layer=60, texttype=0))
add0.add(gdstk.Label('VDD', (14.4,-49.2), layer=60, texttype=0))
add0.add(gdstk.Label('SQ', (92.4,-28.4), layer=59, texttype=0))
add0.add(gdstk.Label('RQ-1', (66,-24), layer=59, texttype=0))
add0.add(gdstk.Label('___\rRQ-1', (86.4,-19.6), layer=59, texttype=0))
add0.add(gdstk.Label('A', (26.8,0.4), layer=59, texttype=0))
add0.add(gdstk.Label('_\rB', (13.2,1.8), layer=59, texttype=0))
add0.add(gdstk.Label('B', (31,0.4), layer=59, texttype=0))
add0.add(gdstk.Label('_\rA', (18,1.8), layer=59, texttype=0))
add0.add(gdstk.Label('SQ+2', (98,-80), layer=59, texttype=0))
add0.add(gdstk.Label('AOXB', (41,-17.6), layer=59, texttype=0))
add0.add(gdstk.Label('RQ', (85.2,-89.6), layer=59, texttype=0))
add0.add(gdstk.Label('SQ+2', (108,-86), layer=59, texttype=0))
add0.add(gdstk.Label('__\rRQ', (90.8,-72), layer=59, texttype=0))

cell = lib.new_cell('CELL')
cell.add(gdstk.Reference(fonct0, (0,0)))
cell.add(gdstk.Reference(add0, (108,0)))

lib.write_gds('CELL.gds')
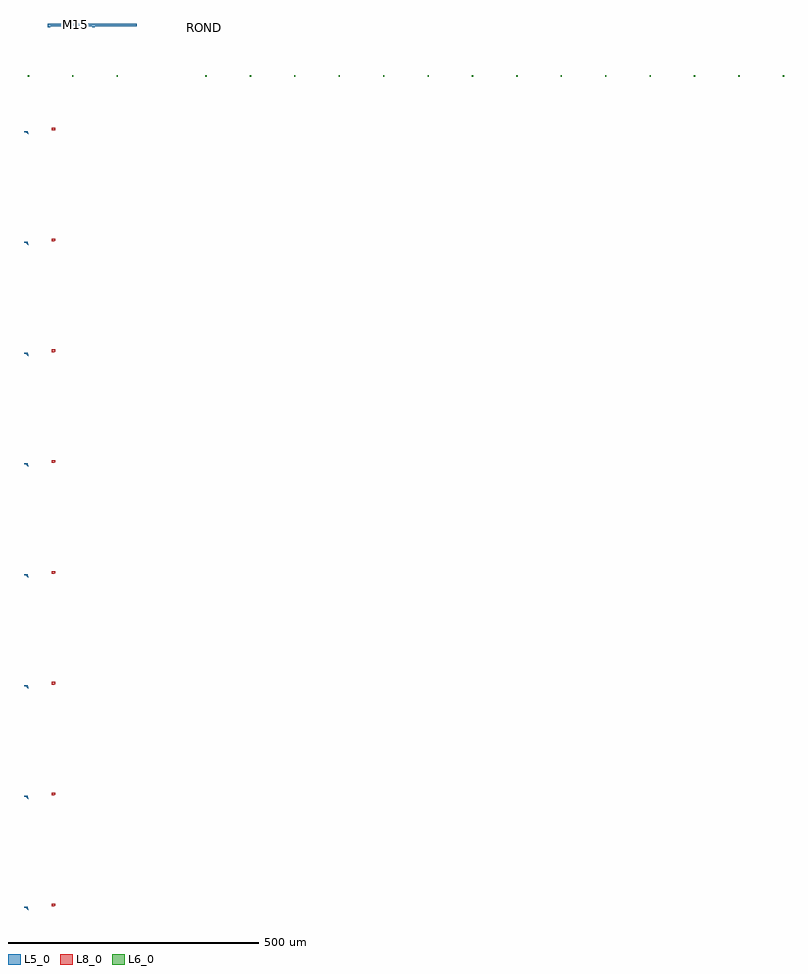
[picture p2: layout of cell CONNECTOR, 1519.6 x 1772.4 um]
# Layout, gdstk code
import gdstk
lib = gdstk.Library(unit=1e-6, precision=1e-09)
def R(c, l, rs):  # rectangles x0, y0, x1, y1
    for r in rs: c.add(gdstk.rectangle(r[:2], r[2:], *l))
def P(c, l, *ps):  # polygons
    for p in ps: c.add(gdstk.Polygon(p, *l))
L5_0 = (5, 0)
L6_0 = (6, 0)
L8_0 = (8, 0)

svabg = lib.new_cell('SVABG')
P(svabg, L5_0, [(0,6.8),(0,4.8),(3.2,4.8),(8,0),(8,3.2),(7.6,3.2),(7.6,6.8)])
P(svabg, L8_0, [(62.8,13.2),(62.8,8.8),(60,8.8),(60,8),(55.6,8),(55.6,13.2)])

contact = lib.new_cell('CONTACT')
R(contact, L6_0, [(0,0,2.4,2.4)])

misa0h = lib.new_cell('MISA0H')
r = gdstk.Reference(contact, (-86.8,3.2)); r.repetition = gdstk.Repetition(14, 1, v1=(88.8,0), v2=(0,0)); misa0h.add(r)
r = gdstk.Reference(contact, (-442,3.2)); r.repetition = gdstk.Repetition(3, 1, v1=(88.8,0), v2=(0,0)); misa0h.add(r)

connector = lib.new_cell('CONNECTOR')
P(connector, L5_0, [(52.8,1767.6),(52.8,1765.6),(47.6,1765.6),(47.6,1772.4),(225.2,1772.4),(225.2,1767.6),(141.6,1767.6),(141.6,1765.6),(136.4,1765.6),(136.4,1767.6)])
r = gdstk.Reference(svabg, (0,0)); r.repetition = gdstk.Repetition(1, 8, v1=(0,0), v2=(0,221.6)); connector.add(r)
connector.add(gdstk.Reference(misa0h, (449.6,1663.6)))
connector.add(gdstk.Label('M15', (103.2,1770), layer=59, texttype=0))
connector.add(gdstk.Label('ROND\r', (361.2,1765.6), layer=60, texttype=0))

lib.write_gds('CONNECTOR.gds')
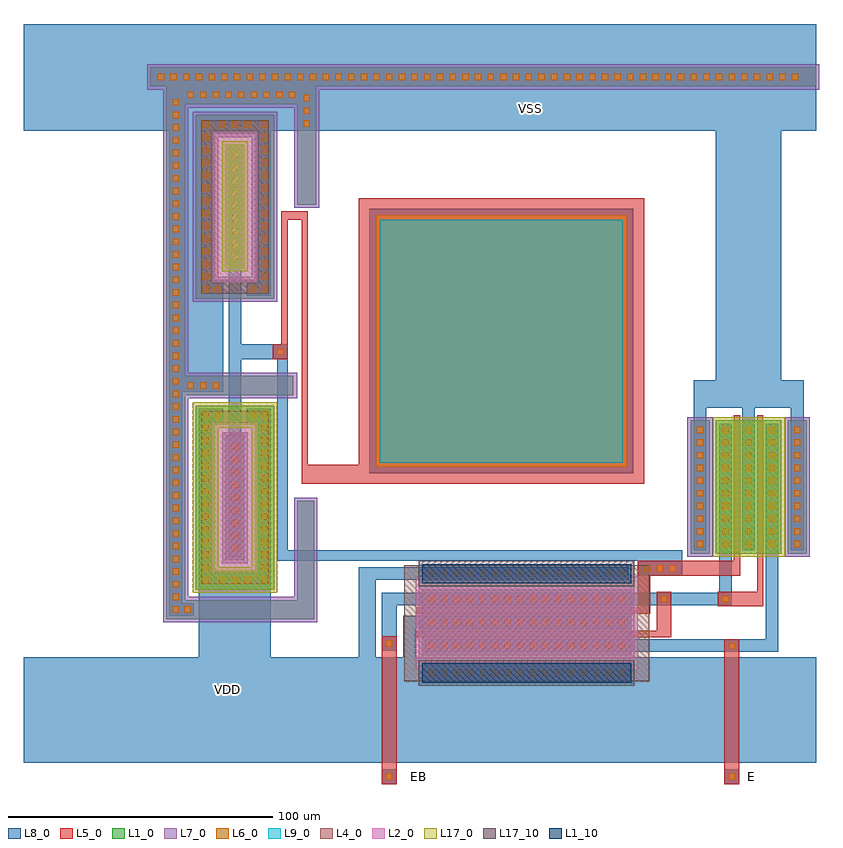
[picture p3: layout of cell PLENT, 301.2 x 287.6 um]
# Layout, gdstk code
from math import pi, radians
import gdstk
lib = gdstk.Library(unit=1e-6, precision=1e-09)
def R(c, l, rs):  # rectangles x0, y0, x1, y1
    for r in rs: c.add(gdstk.rectangle(r[:2], r[2:], *l))
def P(c, l, *ps):  # polygons
    for p in ps: c.add(gdstk.Polygon(p, *l))
L1_0 = (1, 0)
L1_10 = (1, 10)
L2_0 = (2, 0)
L4_0 = (4, 0)
L5_0 = (5, 0)
L6_0 = (6, 0)
L7_0 = (7, 0)
L8_0 = (8, 0)
L9_0 = (9, 0)
L17_0 = (17, 0)
L17_10 = (17, 10)

contact = lib.new_cell('CONTACT')
R(contact, L6_0, [(0,0,2.4,2.4)])

plot = lib.new_cell('PLOT')
R(plot, L5_0, [(0,0,108,108)])
R(plot, L6_0, [(6.4,6.4,101.6,101.6)])
R(plot, L8_0, [(4,4,104,104)])
R(plot, L9_0, [(8,8,100,100)])

plent = lib.new_cell('PLENT')
R(plent, L1_0, [(102.8,30.8,182,55.6), (28.4,66.8,35.6,114), (204.4,69.2,211.6,119.6), (214,69.2,238.8,119.6), (241.2,69.2,248.4,119.6), (28.4,177.2,35.6,224), (0,246,252,253.2)])
P(plent, L1_0, [(17.2,235.2),(17.2,165.6),(46.8,165.6),(46.8,172.8),(24.4,172.8),(24.4,228),(39.6,228),(39.6,172.8),(46.8,172.8),(46.8,235.2)],
  [(13.2,150),(13.2,239.2),(55.6,239.2),(55.6,201.2),(62.8,201.2),(62.8,246),(6,246),(6,150)],
  [(6,150),(6,44.4),(62,44.4),(62,89.2),(55.6,89.2),(55.6,51.6),(13.2,51.6),(13.2,129.2),(54,129.2),(54,136.4),(13.2,136.4),(13.2,150)],
  [(46.8,55.6),(17.2,55.6),(17.2,125.2),(39.6,125.2),(39.6,118),(24.4,118),(24.4,62.8),(39.6,62.8),(39.6,125.2),(46.8,125.2)])
R(plent, L1_10, [(102.8,20.4,182,27.6), (102.8,58,182,65.2)])
R(plent, L2_0, [(100.4,25.2,184.4,60.4), (23.6,62,40.4,118.8), (23.6,172,40.4,228.8)])
R(plent, L4_0, [(96,20.8,188.8,64.8), (19.2,57.6,44.8,123.2), (19.2,167.6,44.8,233.2)])
R(plent, L5_0, [(87.6,-18,93.2,38), (217.2,-18,222.8,36.8)])
P(plent, L5_0, [(189.2,46.4),(100.8,46.4),(100.8,48.8),(184.4,48.8),(184.4,60.8),(189.2,60.8)],
  [(229.6,54.8),(229.6,121.6),(232,121.6),(232,49.2),(214.8,49.2),(214.8,54.8)],
  [(191.6,40),(191.6,54.8),(197.2,54.8),(197.2,37.6),(100.8,37.6),(100.8,40)],
  [(78.8,102.8),(59.6,102.8),(59.6,198.8),(49.6,198.8),(49.6,148.4),(46.4,148.4),(46.4,142.8),(52,142.8),(52,195.6),(57.2,195.6),(57.2,95.6),(78.8,95.6)],
  [(223.2,121.6),(223.2,60.8),(184.4,60.8),(184.4,66.4),(220.8,66.4),(220.8,121.6)])
R(plent, L6_0, [(89.2,-16.4,91.6,-14), (218.8,-16.4,221.2,-14), (218.8,33.2,221.2,35.2), (89.2,34,91.6,36.4), (48,144.4,50.4,146.8)])
R(plent, L7_0, [(101.6,29.6,183.2,56.8), (27.2,65.6,36.8,115.2), (203.2,68,212.8,120.8), (240,68,249.6,120.8), (-1.2,244.8,253.2,254.4)])
P(plent, L7_0, [(16,236.4),(16,164.4),(48,164.4),(48,174),(25.6,174),(25.6,226.8),(38.4,226.8),(38.4,174),(48,174),(48,236.4)],
  [(14.4,150),(14.4,238),(54.4,238),(54.4,200),(64,200),(64,244.8),(4.8,244.8),(4.8,150)],
  [(4.8,150),(4.8,43.2),(63.2,43.2),(63.2,90.4),(54.4,90.4),(54.4,52.8),(14.4,52.8),(14.4,128),(55.6,128),(55.6,137.6),(14.4,137.6),(14.4,150)])
R(plent, L8_0, [(87.6,-18,93.2,-12.4), (217.2,-18,222.8,-12.4), (104,32,237.6,36.8), (232.8,36.8,237.6,118.4), (215.2,54.4,220,118.4), (224,70.4,228.8,124.4), (242.4,70.4,247.2,124.4)])
P(plent, L8_0, [(252,30),(252,-10),(-48,-10),(-48,30),(18.4,30),(18.4,124),(27.6,124),(27.6,119.2),(23.2,119.2),(23.2,61.6),(40.8,61.6),(40.8,119.2),(36.4,119.2),(36.4,124),(45.6,124),(45.6,30)],
  [(252,269.6),(252,229.2),(45.6,229.2),(45.6,166.8),(36.4,166.8),(36.4,171.6),(40.8,171.6),(40.8,229.2),(23.2,229.2),(23.2,171.6),(27.6,171.6),(27.6,130.4),(12,130.4),(12,50.4),(16.4,50.4),(16.4,45.6),(7.2,45.6),(7.2,229.2),(-48,229.2),(-48,269.6)],
  [(95.6,30),(95.6,45.6),(180.8,45.6),(180.8,40.8),(100.4,40.8),(100.4,30)],
  [(87.6,54.4),(220,54.4),(220,49.6),(93.2,49.6),(93.2,32.4),(87.6,32.4)],
  [(180.8,64),(180.8,59.2),(85.2,59.2),(85.2,30),(78.8,30),(78.8,64)],
  [(214,134.8),(214,229.2),(238.8,229.2),(238.8,134.8),(247.2,134.8),(247.2,124.4),(210.4,124.4),(210.4,70.4),(205.6,70.4),(205.6,134.8)],
  [(184.4,66.4),(48,66.4),(48,142.8),(34.4,142.8),(34.4,68),(29.6,68),(29.6,222.8),(34.4,222.8),(34.4,148.4),(52,148.4),(52,70.4),(201.2,70.4),(201.2,60.8),(184.4,60.8)])
R(plent, L17_0, [(212.8,68,240,120.8), (27.2,176,36.8,225.2)])
P(plent, L17_0, [(48,54.4),(16,54.4),(16,126.4),(38.4,126.4),(38.4,116.8),(25.6,116.8),(25.6,64),(38.4,64),(38.4,126.4),(48,126.4)])
R(plent, L17_10, [(101.6,19.2,183.2,28.8), (101.6,56.8,183.2,66.4)])
r = gdstk.Reference(contact, (186.8,62.4)); r.repetition = gdstk.Repetition(3, 1, v1=(4.8,0), v2=(0,0)); plent.add(r)
r = gdstk.Reference(contact, (234,71.6)); r.repetition = gdstk.Repetition(1, 10, v1=(0,0), v2=(0,4.8)); plent.add(r)
plent.add(gdstk.Reference(contact, (24,168)))
r = gdstk.Reference(contact, (42,168)); r.repetition = gdstk.Repetition(1, 14, v1=(0,0), v2=(0,4.8)); plent.add(r)
plent.add(gdstk.Reference(contact, (37.6,168)))
r = gdstk.Reference(contact, (26,230.4)); r.repetition = gdstk.Repetition(3, 1, v1=(4.8,0), v2=(0,0)); plent.add(r)
r = gdstk.Reference(contact, (42,122.8), x_reflection=True); r.repetition = gdstk.Repetition(1, 14, v1=(0,0), v2=(0,-4.8)); plent.add(r)
r = gdstk.Reference(contact, (26,60.4), x_reflection=True); r.repetition = gdstk.Repetition(3, 1, v1=(4.8,0), v2=(0,0)); plent.add(r)
plent.add(gdstk.Reference(contact, (37.6,122.8), x_reflection=True))
r = gdstk.Reference(contact, (30.8,110.8), x_reflection=True); r.repetition = gdstk.Repetition(1, 9, v1=(0,0), v2=(0,-4.8)); plent.add(r)
plent.add(gdstk.Reference(contact, (12.8,46.8)))
r = gdstk.Reference(contact, (14,131.6)); r.repetition = gdstk.Repetition(3, 1, v1=(4.8,0), v2=(0,0)); plent.add(r)
r = gdstk.Reference(contact, (58,230.8)); r.repetition = gdstk.Repetition(1, 3, v1=(0,0), v2=(0,4.8)); plent.add(r)
r = gdstk.Reference(contact, (14,241.6)); r.repetition = gdstk.Repetition(9, 1, v1=(4.8,0), v2=(0,0)); plent.add(r)
r = gdstk.Reference(contact, (225.2,71.6)); r.repetition = gdstk.Repetition(1, 10, v1=(0,0), v2=(0,4.8)); plent.add(r)
plent.add(gdstk.Reference(contact, (193.2,50.8)))
r = gdstk.Reference(contact, (216.4,71.6)); r.repetition = gdstk.Repetition(1, 10, v1=(0,0), v2=(0,4.8)); plent.add(r)
r = gdstk.Reference(contact, (19.6,168)); r.repetition = gdstk.Repetition(1, 14, v1=(0,0), v2=(0,4.8)); plent.add(r)
plent.add(gdstk.Reference(contact, (216.4,50.8)))
r = gdstk.Reference(contact, (179.6,33.2), rotation=pi/2); r.repetition = gdstk.Repetition(1, 16, v1=(0,0), v2=(-4.8,0)); plent.add(r)
r = gdstk.Reference(contact, (179.6,42), rotation=pi/2); r.repetition = gdstk.Repetition(1, 16, v1=(0,0), v2=(-4.8,0)); plent.add(r)
r = gdstk.Reference(contact, (179.6,50.8), rotation=pi/2); r.repetition = gdstk.Repetition(1, 16, v1=(0,0), v2=(-4.8,0)); plent.add(r)
r = gdstk.Reference(contact, (179.6,60.4), rotation=pi/2); r.repetition = gdstk.Repetition(1, 16, v1=(0,0), v2=(-4.8,0)); plent.add(r)
r = gdstk.Reference(contact, (30.8,180.4)); r.repetition = gdstk.Repetition(1, 9, v1=(0,0), v2=(0,4.8)); plent.add(r)
r = gdstk.Reference(contact, (19.6,122.8), x_reflection=True); r.repetition = gdstk.Repetition(1, 14, v1=(0,0), v2=(0,-4.8)); plent.add(r)
plent.add(gdstk.Reference(contact, (24,122.8), x_reflection=True))
r = gdstk.Reference(contact, (8.4,46.8)); r.repetition = gdstk.Repetition(1, 41, v1=(0,0), v2=(0,4.8)); plent.add(r)
plent.add(gdstk.Reference(plot, (78.8,95.6)))
r = gdstk.Reference(contact, (179.6,22.8), rotation=pi/2); r.repetition = gdstk.Repetition(1, 16, v1=(0,0), v2=(-4.8,0)); plent.add(r)
r = gdstk.Reference(contact, (206.8,71.6)); r.repetition = gdstk.Repetition(1, 10, v1=(0,0), v2=(0,4.8)); plent.add(r)
r = gdstk.Reference(contact, (243.6,71.6)); r.repetition = gdstk.Repetition(1, 10, v1=(0,0), v2=(0,4.8)); plent.add(r)
r = gdstk.Reference(contact, (2.8,248.4)); r.repetition = gdstk.Repetition(51, 1, v1=(4.8,0), v2=(0,0)); plent.add(r)
plent.add(gdstk.Label('EB', (101.6,-15.2), layer=59, texttype=0))
plent.add(gdstk.Label('E', (227.6,-15.2), layer=59, texttype=0))
plent.add(gdstk.Label('VSS', (143.7,237.7), layer=60, texttype=0))
plent.add(gdstk.Label('VDD', (29,17.7), layer=60, texttype=0))

lib.write_gds('PLENT.gds')
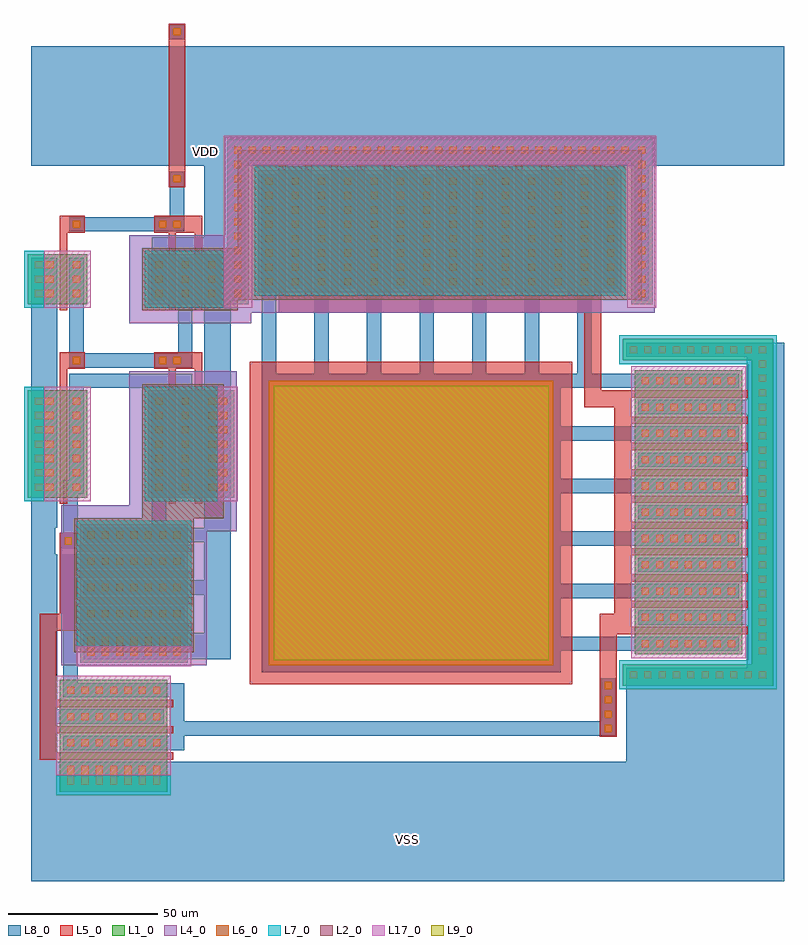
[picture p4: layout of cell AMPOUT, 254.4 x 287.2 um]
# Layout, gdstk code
import gdstk
lib = gdstk.Library(unit=1e-6, precision=1e-09)
def R(c, l, rs):  # rectangles x0, y0, x1, y1
    for r in rs: c.add(gdstk.rectangle(r[:2], r[2:], *l))
def A(c, l, x, y, w, h, nx, ny, dx, dy):  # array of equal rectangles
    R(c, l, [(x+i*dx, y+j*dy, x+i*dx+w, y+j*dy+h) for i in range(nx) for j in range(ny)])
def P(c, l, *ps):  # polygons
    for p in ps: c.add(gdstk.Polygon(p, *l))
L1_0 = (1, 0)
L2_0 = (2, 0)
L4_0 = (4, 0)
L5_0 = (5, 0)
L6_0 = (6, 0)
L7_0 = (7, 0)
L8_0 = (8, 0)
L9_0 = (9, 0)
L17_0 = (17, 0)

plot = lib.new_cell('PLOT')
R(plot, L5_0, [(0,0,108,108)])
R(plot, L6_0, [(6.4,6.4,101.6,101.6)])
R(plot, L8_0, [(4,4,104,104)])
R(plot, L9_0, [(8,8,100,100)])

contact = lib.new_cell('CONTACT')
R(contact, L6_0, [(0,0,2.4,2.4)])

ampout = lib.new_cell('AMPOUT')
R(ampout, L1_0, [(9.6,30,45.6,67.6), (16.4,73.2,52.4,119.6), (202,76,238,171.2), (-1.2,128.4,18.8,164.4), (39.2,128.4,68,164.4), (-1.2,193.2,18.8,210), (39.2,193.2,65.6,210), (76,197.2,197.6,238)])
P(ampout, L1_0, [(241.2,72.8),(241.2,174.4),(198,174.4),(198,181.6),(248.4,181.6),(248.4,65.6),(198,65.6),(198,72.8)],
  [(208,248.4),(208,193.2),(200.8,193.2),(200.8,241.2),(72.8,241.2),(72.8,193.2),(65.6,193.2),(65.6,248.4)])
R(ampout, L2_0, [(14.4,76.8,54.4,121.6), (37.2,121.6,64.4,166.4)])
P(ampout, L2_0, [(69.2,212),(69.2,244.8),(204.4,244.8),(204.4,194.8),(69.2,194.8),(69.2,191.2),(37.2,191.2),(37.2,212)])
P(ampout, L4_0, [(68.8,170.8),(32.8,170.8),(32.8,126),(10,126),(10,72.4),(58.8,72.4),(58.8,117.2),(68.8,117.2)],
  [(208.8,249.2),(64.8,249.2),(64.8,216.4),(32.8,216.4),(32.8,186.8),(73.6,186.8),(73.6,190.4),(208.8,190.4)])
R(ampout, L5_0, [(46,232.4,51.6,287.2)])
P(ampout, L5_0, [(200.8,153.2),(200.8,146.8),(195.2,146.8),(195.2,164.4),(240,164.4),(240,162),(200.8,162),(200.8,155.6),(240,155.6),(240,153.2)],
  [(200.8,135.6),(200.8,129.2),(195.2,129.2),(195.2,146.8),(240,146.8),(240,144.4),(200.8,144.4),(200.8,138),(240,138),(240,135.6)],
  [(200.8,118),(200.8,111.6),(195.2,111.6),(195.2,129.2),(240,129.2),(240,126.8),(200.8,126.8),(200.8,120.4),(240,120.4),(240,118)],
  [(200.8,100.4),(200.8,94),(195.2,94),(195.2,111.6),(240,111.6),(240,109.2),(200.8,109.2),(200.8,102.8),(240,102.8),(240,100.4)],
  [(54.8,171.6),(48.4,171.6),(48.4,177.2),(57.2,177.2),(57.2,126.4),(54.8,126.4)],
  [(15.2,101.6),(15.2,95.2),(9.6,95.2),(9.6,104),(54.4,104),(54.4,101.6)],
  [(94,196),(100.4,196),(100.4,190.4),(82.8,190.4),(82.8,240),(85.2,240),(85.2,196),(91.6,196),(91.6,240),(94,240)],
  [(111.6,196),(118,196),(118,190.4),(100.4,190.4),(100.4,240),(102.8,240),(102.8,196),(109.2,196),(109.2,240),(111.6,240)],
  [(129.2,196),(135.6,196),(135.6,190.4),(118,190.4),(118,240),(120.4,240),(120.4,196),(126.8,196),(126.8,240),(129.2,240)],
  [(146.8,196),(153.2,196),(153.2,190.4),(135.6,190.4),(135.6,240),(138,240),(138,196),(144.4,196),(144.4,240),(146.8,240)],
  [(164.4,196),(170.8,196),(170.8,190.4),(153.2,190.4),(153.2,240),(155.6,240),(155.6,196),(162,196),(162,240),(164.4,240)],
  [(182,196),(188.4,196),(188.4,190.4),(170.8,190.4),(170.8,240),(173.2,240),(173.2,196),(179.6,196),(179.6,240),(182,240)],
  [(46,171.6),(41.2,171.6),(41.2,177.2),(48.4,177.2),(48.4,126.4),(46,126.4)],
  [(9.6,104),(9.6,116.8),(15.2,116.8),(15.2,112.8),(54.4,112.8),(54.4,110.4),(15.2,110.4),(15.2,104)],
  [(8.4,58.4),(8.4,52),(2.8,52),(2.8,60.8),(47.6,60.8),(47.6,58.4)],
  [(47.6,40.8),(2.8,40.8),(2.8,52),(47.6,52),(47.6,49.6),(8.4,49.6),(8.4,43.2),(47.6,43.2)],
  [(190.8,164.4),(195.2,164.4),(195.2,158.8),(185.2,158.8),(185.2,190.4),(188.4,190.4),(188.4,240),(190.8,240)],
  [(196,82.8),(196,48.4),(190.4,48.4),(190.4,89.6),(195.2,89.6),(195.2,94),(240,94),(240,91.6),(200.8,91.6),(200.8,85.2),(240,85.2),(240,82.8)],
  [(8.4,84),(8.4,60.8),(2.8,60.8),(2.8,89.6),(9.6,89.6),(9.6,95.2),(54.4,95.2),(54.4,92.8),(15.2,92.8),(15.2,86.4),(54.4,86.4),(54.4,84)],
  [(9.6,126.4),(9.6,177.2),(18,177.2),(18,171.6),(12,171.6),(12,126.4)],
  [(54.8,217.2),(48.4,217.2),(48.4,222.8),(57.2,222.8),(57.2,191.2),(54.8,191.2)],
  [(46,217.2),(41.2,217.2),(41.2,222.8),(48.4,222.8),(48.4,191.2),(46,191.2)],
  [(9.6,191.2),(9.6,222.8),(18,222.8),(18,217.2),(12,217.2),(12,191.2)])
A(ampout, L6_0, 12, 32.4, 2.4, 6.4, 7, 1, 4.8, 0)
A(ampout, L6_0, 12, 45.2, 2.4, 2.4, 7, 3, 4.8, 8.8)
A(ampout, L6_0, 192, 50, 2.4, 2.4, 1, 4, 0, 4.8)
A(ampout, L6_0, 200.4, 68, 2.4, 2.4, 10, 2, 4.8, 108.8)
A(ampout, L6_0, 18.8, 75.6, 2.4, 6.4, 7, 1, 4.8, 0)
A(ampout, L6_0, 243.6, 76, 2.4, 2.4, 1, 21, 0, 4.8)
A(ampout, L6_0, 204.4, 78.4, 2.4, 2.4, 7, 11, 4.8, 8.8)
A(ampout, L6_0, 18.8, 88.4, 2.4, 2.4, 7, 4, 4.8, 8.8)
A(ampout, L6_0, 1.2, 130.8, 6.4, 2.4, 1, 7, 0, 4.8)
A(ampout, L6_0, 14, 130.8, 2.4, 2.4, 1, 7, 0, 4.8)
A(ampout, L6_0, 41.6, 130.8, 2.4, 2.4, 1, 7, 0, 4.8)
A(ampout, L6_0, 50.4, 130.8, 2.4, 2.4, 1, 7, 0, 4.8)
A(ampout, L6_0, 59.2, 130.8, 6.4, 2.4, 1, 7, 0, 4.8)
A(ampout, L6_0, 1.2, 195.6, 6.4, 2.4, 1, 3, 0, 4.8)
A(ampout, L6_0, 14, 195.6, 2.4, 2.4, 1, 3, 0, 4.8)
A(ampout, L6_0, 41.6, 195.6, 2.4, 2.4, 4, 3, 8.8, 4.8)
A(ampout, L6_0, 203.2, 195.6, 2.4, 2.4, 1, 11, 0, 4.8)
A(ampout, L6_0, 78.4, 199.6, 2.4, 2.4, 14, 8, 8.8, 4.8)
A(ampout, L6_0, 68, 210, 2.4, 2.4, 1, 7, 0, 4.8)
A(ampout, L6_0, 68, 243.6, 2.4, 2.4, 28, 1, 4.8, 0)
R(ampout, L6_0, [(11.2,112.8,13.6,115.2), (14,173.2,16.4,175.6), (42.8,173.2,45.2,175.6), (47.6,173.2,50,175.6), (14,218.8,16.4,221.2), (42.8,218.8,45.2,221.2), (47.6,218.8,50,221.2), (47.6,234,50,236.4)])
R(ampout, L7_0, [(8.4,28.8,46.8,35.6), (15.2,78.8,53.6,120.8), (-2.4,127.2,4.4,165.6), (38,127.2,62.4,165.6), (-2.4,192,4.4,211.2), (38,192,64.4,211.2), (74.8,196,198.8,239.2)])
P(ampout, L7_0, [(249.6,64.4),(196.8,64.4),(196.8,74),(240,74),(240,173.2),(196.8,173.2),(196.8,182.8),(249.6,182.8)])
A(ampout, L8_0, 177.2, 77.2, 59.6, 4.8, 1, 6, 0, 17.6)
A(ampout, L8_0, 203.2, 86, 36.4, 4.8, 1, 5, 0, 17.6)
A(ampout, L8_0, 77.2, 170, 4.8, 66.8, 7, 1, 17.6, 0)
A(ampout, L8_0, 86, 198.4, 4.8, 41.2, 7, 1, 17.6, 0)
R(ampout, L8_0, [(46,282,51.6,286.8)])
P(ampout, L8_0, [(15.6,104.8),(51.2,104.8),(51.2,109.6),(10.8,109.6),(10.8,87.2),(51.2,87.2),(51.2,92),(15.6,92)],
  [(190.8,53.6),(190.8,68),(195.6,68),(195.6,48.8),(51.2,48.8),(51.2,44),(10.8,44),(10.8,48.8),(46.4,48.8),(46.4,61.6),(10.8,61.6),(10.8,87.2),(15.6,87.2),(15.6,66.4),(51.2,66.4),(51.2,53.6)],
  [(8.8,109.6),(8,109.6),(8,118.4),(8.8,118.4),(8.8,208.8),(0,208.8),(0,0),(252,0),(252,180.4),(199.2,180.4),(199.2,175.6),(239.6,175.6),(239.6,71.6),(199.2,71.6),(199.2,40),(8.8,40),(8.8,52.8),(44.4,52.8),(44.4,57.6),(8.8,57.6)],
  [(15.6,111.6),(10,111.6),(10,116.4),(10.8,116.4),(10.8,134.4),(12.8,134.4),(12.8,170),(54,170),(54,129.6),(49.2,129.6),(49.2,165.2),(17.6,165.2),(17.6,129.6),(15.6,129.6)],
  [(45.2,210.8),(45.2,194.4),(40.4,194.4),(40.4,215.6),(58,215.6),(58,239.6),(0,239.6),(0,279.6),(252,279.6),(252,239.6),(206.8,239.6),(206.8,194.4),(202,194.4),(202,239.6),(71.6,239.6),(71.6,194.4),(66.8,194.4),(66.8,74.4),(17.6,74.4),(17.6,83.2),(58,83.2),(58,96),(17.6,96),(17.6,100.8),(58,100.8),(58,113.6),(17.6,113.6),(17.6,118.4),(40.4,118.4),(40.4,163.2),(45.2,163.2),(45.2,118.4),(58,118.4),(58,210.8)],
  [(12.8,172),(12.8,208.8),(17.6,208.8),(17.6,176.8),(49.2,176.8),(49.2,208.8),(54,208.8),(54,172)],
  [(12.8,222.4),(12.8,217.6),(51.2,217.6),(51.2,237.6),(46.4,237.6),(46.4,222.4)])
R(ampout, L17_0, [(8.4,35.6,46.8,68.8), (15.2,72,53.6,78.8), (200.8,74.8,239.2,172.4), (4.4,127.2,20,165.6), (62.4,127.2,69.2,165.6), (4.4,192,20,211.2)])
P(ampout, L17_0, [(209.2,249.6),(209.2,192),(199.6,192),(199.6,240),(74,240),(74,192),(64.4,192),(64.4,249.6)])
ampout.add(gdstk.Reference(plot, (73.2,66)))
ampout.add(gdstk.Reference(contact, (47.6,283.2)))
ampout.add(gdstk.Label('VDD', (58.4,244.4), layer=60, texttype=0))
ampout.add(gdstk.Label('VSS', (126,14), layer=60, texttype=0))

lib.write_gds('AMPOUT.gds')
